VERSION 5.7 ;
BUSBITCHARS "[]" ;
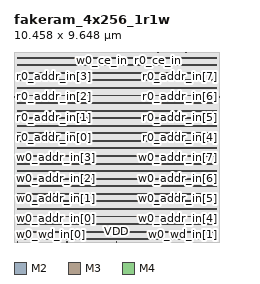
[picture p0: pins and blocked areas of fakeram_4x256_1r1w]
MACRO fakeram_4x256_1r1w
  FOREIGN fakeram_4x256_1r1w 0 0 ;
  SYMMETRY X Y R90 ;
  SIZE 10.458 BY 9.648 ;
  CLASS BLOCK ;
  PIN w0_wd_in[0]
    DIRECTION INPUT ;
    USE SIGNAL ;
    SHAPE ABUTMENT ;
    PORT
      LAYER M2 ;
      RECT 0.000 0.138 0.036 0.150 ;
    END
  END w0_wd_in[0]
  PIN w0_wd_in[1]
    DIRECTION INPUT ;
    USE SIGNAL ;
    SHAPE ABUTMENT ;
    PORT
      LAYER M2 ;
      RECT 10.422 0.138 10.458 0.150 ;
    END
  END w0_wd_in[1]
  PIN w0_wd_in[2]
    DIRECTION INPUT ;
    USE SIGNAL ;
    SHAPE ABUTMENT ;
    PORT
      LAYER M3 ;
      RECT 0.161 0.000 0.175 0.042 ;
    END
  END w0_wd_in[2]
  PIN w0_wd_in[3]
    DIRECTION INPUT ;
    USE SIGNAL ;
    SHAPE ABUTMENT ;
    PORT
      LAYER M3 ;
      RECT 2.681 0.000 2.695 0.042 ;
    END
  END w0_wd_in[3]
  PIN r0_rd_out[0]
    DIRECTION OUTPUT ;
    USE SIGNAL ;
    SHAPE ABUTMENT ;
    PORT
      LAYER M3 ;
      RECT 5.201 0.000 5.215 0.042 ;
    END
  END r0_rd_out[0]
  PIN r0_rd_out[1]
    DIRECTION OUTPUT ;
    USE SIGNAL ;
    SHAPE ABUTMENT ;
    PORT
      LAYER M3 ;
      RECT 7.721 0.000 7.735 0.042 ;
    END
  END r0_rd_out[1]
  PIN r0_rd_out[2]
    DIRECTION OUTPUT ;
    USE SIGNAL ;
    SHAPE ABUTMENT ;
    PORT
      LAYER M3 ;
      RECT 0.161 9.606 0.175 9.648 ;
    END
  END r0_rd_out[2]
  PIN r0_rd_out[3]
    DIRECTION OUTPUT ;
    USE SIGNAL ;
    SHAPE ABUTMENT ;
    PORT
      LAYER M3 ;
      RECT 1.589 9.606 1.603 9.648 ;
    END
  END r0_rd_out[3]
  PIN w0_addr_in[0]
    DIRECTION INPUT ;
    USE SIGNAL ;
    SHAPE ABUTMENT ;
    PORT
      LAYER M2 ;
      RECT 0.000 1.170 0.036 1.182 ;
    END
  END w0_addr_in[0]
  PIN w0_addr_in[1]
    DIRECTION INPUT ;
    USE SIGNAL ;
    SHAPE ABUTMENT ;
    PORT
      LAYER M2 ;
      RECT 0.000 2.202 0.036 2.214 ;
    END
  END w0_addr_in[1]
  PIN w0_addr_in[2]
    DIRECTION INPUT ;
    USE SIGNAL ;
    SHAPE ABUTMENT ;
    PORT
      LAYER M2 ;
      RECT 0.000 3.234 0.036 3.246 ;
    END
  END w0_addr_in[2]
  PIN w0_addr_in[3]
    DIRECTION INPUT ;
    USE SIGNAL ;
    SHAPE ABUTMENT ;
    PORT
      LAYER M2 ;
      RECT 0.000 4.266 0.036 4.278 ;
    END
  END w0_addr_in[3]
  PIN w0_addr_in[4]
    DIRECTION INPUT ;
    USE SIGNAL ;
    SHAPE ABUTMENT ;
    PORT
      LAYER M2 ;
      RECT 10.422 1.170 10.458 1.182 ;
    END
  END w0_addr_in[4]
  PIN w0_addr_in[5]
    DIRECTION INPUT ;
    USE SIGNAL ;
    SHAPE ABUTMENT ;
    PORT
      LAYER M2 ;
      RECT 10.422 2.202 10.458 2.214 ;
    END
  END w0_addr_in[5]
  PIN w0_addr_in[6]
    DIRECTION INPUT ;
    USE SIGNAL ;
    SHAPE ABUTMENT ;
    PORT
      LAYER M2 ;
      RECT 10.422 3.234 10.458 3.246 ;
    END
  END w0_addr_in[6]
  PIN w0_addr_in[7]
    DIRECTION INPUT ;
    USE SIGNAL ;
    SHAPE ABUTMENT ;
    PORT
      LAYER M2 ;
      RECT 10.422 4.266 10.458 4.278 ;
    END
  END w0_addr_in[7]
  PIN r0_addr_in[0]
    DIRECTION INPUT ;
    USE SIGNAL ;
    SHAPE ABUTMENT ;
    PORT
      LAYER M2 ;
      RECT 0.000 5.298 0.036 5.310 ;
    END
  END r0_addr_in[0]
  PIN r0_addr_in[1]
    DIRECTION INPUT ;
    USE SIGNAL ;
    SHAPE ABUTMENT ;
    PORT
      LAYER M2 ;
      RECT 0.000 6.330 0.036 6.342 ;
    END
  END r0_addr_in[1]
  PIN r0_addr_in[2]
    DIRECTION INPUT ;
    USE SIGNAL ;
    SHAPE ABUTMENT ;
    PORT
      LAYER M2 ;
      RECT 0.000 7.362 0.036 7.374 ;
    END
  END r0_addr_in[2]
  PIN r0_addr_in[3]
    DIRECTION INPUT ;
    USE SIGNAL ;
    SHAPE ABUTMENT ;
    PORT
      LAYER M2 ;
      RECT 0.000 8.394 0.036 8.406 ;
    END
  END r0_addr_in[3]
  PIN r0_addr_in[4]
    DIRECTION INPUT ;
    USE SIGNAL ;
    SHAPE ABUTMENT ;
    PORT
      LAYER M2 ;
      RECT 10.422 5.298 10.458 5.310 ;
    END
  END r0_addr_in[4]
  PIN r0_addr_in[5]
    DIRECTION INPUT ;
    USE SIGNAL ;
    SHAPE ABUTMENT ;
    PORT
      LAYER M2 ;
      RECT 10.422 6.330 10.458 6.342 ;
    END
  END r0_addr_in[5]
  PIN r0_addr_in[6]
    DIRECTION INPUT ;
    USE SIGNAL ;
    SHAPE ABUTMENT ;
    PORT
      LAYER M2 ;
      RECT 10.422 7.362 10.458 7.374 ;
    END
  END r0_addr_in[6]
  PIN r0_addr_in[7]
    DIRECTION INPUT ;
    USE SIGNAL ;
    SHAPE ABUTMENT ;
    PORT
      LAYER M2 ;
      RECT 10.422 8.394 10.458 8.406 ;
    END
  END r0_addr_in[7]
  PIN w0_we_in
    DIRECTION INPUT ;
    USE SIGNAL ;
    SHAPE ABUTMENT ;
    PORT
      LAYER M3 ;
      RECT 3.017 9.606 3.031 9.648 ;
    END
  END w0_we_in
  PIN w0_ce_in
    DIRECTION INPUT ;
    USE SIGNAL ;
    SHAPE ABUTMENT ;
    PORT
      LAYER M3 ;
      RECT 4.445 9.606 4.459 9.648 ;
    END
  END w0_ce_in
  PIN w0_clk
    DIRECTION INPUT ;
    USE SIGNAL ;
    SHAPE ABUTMENT ;
    PORT
      LAYER M3 ;
      RECT 5.873 9.606 5.887 9.648 ;
    END
  END w0_clk
  PIN r0_ce_in
    DIRECTION INPUT ;
    USE SIGNAL ;
    SHAPE ABUTMENT ;
    PORT
      LAYER M3 ;
      RECT 7.301 9.606 7.315 9.648 ;
    END
  END r0_ce_in
  PIN r0_clk
    DIRECTION INPUT ;
    USE SIGNAL ;
    SHAPE ABUTMENT ;
    PORT
      LAYER M3 ;
      RECT 8.729 9.606 8.743 9.648 ;
    END
  END r0_clk
  PIN VSS
    DIRECTION INOUT ;
    USE GROUND ;
    PORT
      LAYER M4 ;
      RECT 0.168 0.120 10.290 0.168 ;
      RECT 0.168 0.504 10.290 0.552 ;
      RECT 0.168 0.888 10.290 0.936 ;
      RECT 0.168 1.272 10.290 1.320 ;
      RECT 0.168 1.656 10.290 1.704 ;
      RECT 0.168 2.040 10.290 2.088 ;
      RECT 0.168 2.424 10.290 2.472 ;
      RECT 0.168 2.808 10.290 2.856 ;
      RECT 0.168 3.192 10.290 3.240 ;
      RECT 0.168 3.576 10.290 3.624 ;
      RECT 0.168 3.960 10.290 4.008 ;
      RECT 0.168 4.344 10.290 4.392 ;
      RECT 0.168 4.728 10.290 4.776 ;
      RECT 0.168 5.112 10.290 5.160 ;
      RECT 0.168 5.496 10.290 5.544 ;
      RECT 0.168 5.880 10.290 5.928 ;
      RECT 0.168 6.264 10.290 6.312 ;
      RECT 0.168 6.648 10.290 6.696 ;
      RECT 0.168 7.032 10.290 7.080 ;
      RECT 0.168 7.416 10.290 7.464 ;
      RECT 0.168 7.800 10.290 7.848 ;
      RECT 0.168 8.184 10.290 8.232 ;
      RECT 0.168 8.568 10.290 8.616 ;
      RECT 0.168 8.952 10.290 9.000 ;
      RECT 0.168 9.336 10.290 9.384 ;
    END
  END VSS
  PIN VDD
    DIRECTION INOUT ;
    USE POWER ;
    PORT
      LAYER M4 ;
      RECT 0.168 0.120 10.290 0.168 ;
      RECT 0.168 0.504 10.290 0.552 ;
      RECT 0.168 0.888 10.290 0.936 ;
      RECT 0.168 1.272 10.290 1.320 ;
      RECT 0.168 1.656 10.290 1.704 ;
      RECT 0.168 2.040 10.290 2.088 ;
      RECT 0.168 2.424 10.290 2.472 ;
      RECT 0.168 2.808 10.290 2.856 ;
      RECT 0.168 3.192 10.290 3.240 ;
      RECT 0.168 3.576 10.290 3.624 ;
      RECT 0.168 3.960 10.290 4.008 ;
      RECT 0.168 4.344 10.290 4.392 ;
      RECT 0.168 4.728 10.290 4.776 ;
      RECT 0.168 5.112 10.290 5.160 ;
      RECT 0.168 5.496 10.290 5.544 ;
      RECT 0.168 5.880 10.290 5.928 ;
      RECT 0.168 6.264 10.290 6.312 ;
      RECT 0.168 6.648 10.290 6.696 ;
      RECT 0.168 7.032 10.290 7.080 ;
      RECT 0.168 7.416 10.290 7.464 ;
      RECT 0.168 7.800 10.290 7.848 ;
      RECT 0.168 8.184 10.290 8.232 ;
      RECT 0.168 8.568 10.290 8.616 ;
      RECT 0.168 8.952 10.290 9.000 ;
      RECT 0.168 9.336 10.290 9.384 ;
    END
  END VDD
  OBS
    LAYER M1 ;
    RECT 0 0 10.458 9.648 ;
    LAYER M2 ;
    RECT 0 0 10.458 9.648 ;
    LAYER M3 ;
    RECT 0 0 10.458 9.648 ;
    LAYER M4 ;
    RECT 0 0 10.458 9.648 ;
  END
END fakeram_4x256_1r1w

END LIBRARY
